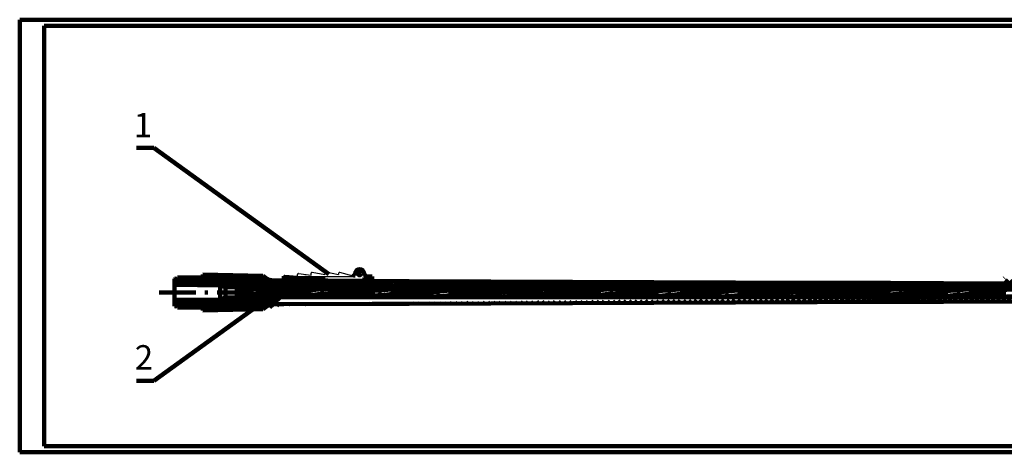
# Model space of a CAD drawing. Units: inches. Extents: x -7.8 to 42.6, y -11.6 to 2.6.
# Drawn here: x -7.8 to 24.5, y -11.6 to 2.6 of the extents above; entities that cross this region are included whole.
import ezdxf

# ---------------------------------------------------------------- set-up
doc = ezdxf.new("R2010")
doc.units = ezdxf.units.IN
doc.header["$LTSCALE"] = 0.1
doc.header["$MEASUREMENT"] = 0
doc.linetypes.add('ACAD_ISO10W100', pattern=[18, 12, -3, 0, -3])

# ---------------------------------------------------------------- blocks, each defined once
blk = doc.blocks.new('_dragoon__1896')
at = {"lineweight": 25, "ltscale": 0.7}
h = blk.add_hatch(dxfattribs=at)
h.set_pattern_fill('ANSI31', scale=0.25, angle=90, style=0)
h.paths.add_polyline_path([(-0.708, -27.192), (-0.708, -27.127), (-1.353, -27.127), (-1.353, -27.187)])
h.paths.add_polyline_path([(-0.708, -27.192), (-0.692, -27.192), (-0.692, -27.127), (-0.708, -27.127)])
h.paths.add_polyline_path([(-0.599, -27.193), (-0.583, -27.193), (-0.583, -27.127), (-0.599, -27.127)])
h.paths.add_polyline_path([(-0.003, -27.198), (-0.003, -27.162), (-0.378, -27.127), (-0.583, -27.127), (-0.583, -27.193)])
h.paths.add_polyline_path([(1.347, -27.068), (1.316, -27.068, -0.044213), (1.297, -27.098), (1.297, -27.207), (1.547, -27.209), (1.547, -27.068)])
at = {"color": 7, "lineweight": 140, "ltscale": 1.4}
for p, q in [((-1.353, -27.187), (-1.353, -27.06)), ((-0.378, -27.127), (-1.353, -27.127)), ((-0.003, -27.162), (-0.378, -27.127)), ((-0.003, -27.198), (-0.003, -27.162)), ((0.987, -27.028), (0.954, -27.028)), ((0.987, -27.028), (0.987, -26.978)), ((1.287, -27.028), (1.287, -26.978)), ((1.287, -27.028), (1.32, -27.028)), ((1.297, -27.098), (1.297, -27.207)), ((1.347, -27.068), (1.316, -27.068)), ((1.347, -27.055), (1.347, -27.068)), ((1.547, -27.068), (1.347, -27.068)), ((1.547, -27.068), (1.547, -27.209)), ((0.447, -27.588), (0.927, -27.588)), ((0.927, -27.588), (1.636, -27.588))]:
    blk.add_line(p, q, dxfattribs=at)
at = {"color": 7, "lineweight": 25, "ltscale": 0.7}
for p, q in [((-1.353, -27.067), (-0.924, -27.067)), ((-0.903, -27.069), (-1.32, -27.03)), ((-0.903, -27.069), (-0.903, -26.999)), ((-0.903, -27.067), (0.483, -27.067)), ((-0.869, -26.969), (-0.453, -27.022)), ((-0.692, -27.127), (-0.692, -27.192)), ((-0.599, -27.127), (-0.599, -27.193)), ((-0.453, -27.022), (-0.453, -26.958)), ((-0.418, -26.928), (-0.003, -26.998)), ((-0.378, -27.127), (-0.333, -27.127)), ((-0.333, -27.127), (-0.373, -27.067)), ((-0.003, -26.944), (-0.003, -26.998)), ((0.034, -26.914), (0.447, -27.005)), ((0.447, -26.964), (0.447, -27.005)), ((0.483, -27.067), (0.915, -27.067)), ((0.927, -27.059), (0.486, -26.935)), ((0.927, -27.055), (0.927, -27.055))]:
    blk.add_line(p, q, dxfattribs=at)
at = {"color": 7, "lineweight": 25, "ltscale": 0.25}
for p, q in [((-0.708, -27.127), (-0.708, -27.192)), ((-0.583, -27.127), (-0.583, -27.193))]:
    blk.add_line(p, q, dxfattribs=at)
at = {"color": 1, "linetype": 'ACAD_ISO10W100', "lineweight": 25, "ltscale": 0.25}
blk.add_line((-0.645, -27.045), (-0.645, -27.277), dxfattribs=at)
at = {"color": 7, "lineweight": 100, "ltscale": 1.4}
for p, q in [((-1.353, -27.199), (-1.353, -27.187)), ((-1.353, -27.187), (1.547, -27.209))]:
    blk.add_line(p, q, dxfattribs=at)
at = {"color": 7, "lineweight": 140, "ltscale": 1.4}
blk.add_circle((1.137, -26.978), 0.05, dxfattribs=at)
for centre, radius, start, end in [((1.137, -26.978), 0.15, 0, 180), ((0.954, -27.055), 0.027, 90, 180), ((1.137, -26.978), 0.2, 323.1301, 333.2563), ((1.32, -27.055), 0.027, 360, 90)]:
    blk.add_arc(centre, radius, start, end, dxfattribs=at)
at = {"color": 7, "lineweight": 25, "ltscale": 0.7}
for centre, radius, start, end in [((-1.323, -27.06), 0.03, 84.6047, 180), ((-0.873, -26.999), 0.03, 82.7183, 180), ((-0.423, -26.958), 0.03, 80.4138, 180), ((0.027, -26.944), 0.03, 77.5926, 180), ((0.477, -26.964), 0.03, 74.2914, 180), ((0.915, -27.055), 0.012, 270, 0)]:
    blk.add_arc(centre, radius, start, end, dxfattribs=at)

msp = doc.modelspace()

# ---------------------------------------------------------------- hatches: boundary and pattern name
at = {"lineweight": 100, "ltscale": 1.4}
h = msp.add_hatch(dxfattribs=at)
h.set_pattern_fill('ANSI31', style=0)
edge = h.paths.add_edge_path()
edge.add_line((-1.22, -6.109), (-2.72, -6.093))
edge.add_line((-2.72, -5.89), (-2.645, -5.89))
edge.add_line((-2.625, -5.85), (-2.645, -5.89))
edge.add_line((-1.789, -5.85), (-2.625, -5.85))
edge.add_line((-1.789, -5.85), (-1.789, -5.749))
edge.add_line((-1.789, -5.749), (0.18, -5.789))
edge.add_arc((0.57, -5.393), 0.556, 225.4044, 270.9928)
edge.add_line((0.58, -5.949), (0.87, -5.95))
edge.add_line((0.87, -5.938), (3.77, -5.96))
edge.add_line((3.77, -5.96), (4.986, -5.965))
edge.add_line((18.386, -6.019), (4.986, -5.965))
edge.add_line((20.8, -6.028), (18.386, -6.019))
edge.add_line((20.8, -6.028), (22.531, -6.034))
edge.add_line((24.533, -6.041), (22.531, -6.034))
edge.add_line((24.533, -6.041), (24.533, -5.864))
edge.add_line((24.675, -5.864), (24.533, -5.864))
edge.add_line((24.675, -5.864), (24.65, -5.944))
edge.add_line((24.65, -5.944), (24.85, -5.944))
edge.add_line((24.85, -5.944), (24.825, -5.864))
edge.add_line((24.825, -5.864), (24.97, -5.864))
edge.add_line((24.97, -6.043), (24.97, -5.864))
edge.add_line((25.955, -6.046), (24.97, -6.043))
edge.add_arc((25.955, -6.121), 0.075, 0, 90)
edge.add_line((26.03, -6.189), (0.16, -6.189))
edge.add_line((0.16, -6.189), (-0.55, -6.183))
edge.add_line((-0.55, -6.183), (-0.67, -6.17))
edge.add_line((-0.67, -6.17), (-1.04, -6.169))
edge.add_line((-1.04, -6.169), (-1.22, -6.109))
h.paths.add_polyline_path([(11.1, -1.279), (12.21, -1.279), (12.21, -1.549), (11.1, -1.549)], flags=9)
h = msp.add_hatch(dxfattribs=at)
h.set_pattern_fill('ANSI31', style=0)
edge = h.paths.add_edge_path()
edge.add_line((-2.72, -6.584), (-2.72, -6.788))
edge.add_line((-2.72, -6.584), (-1.22, -6.569))
edge.add_line((-2.72, -6.788), (-1.789, -6.788))
edge.add_line((-2.625, -6.828), (-2.645, -6.788))
edge.add_line((-1.789, -6.828), (-2.625, -6.828))
edge.add_line((-1.789, -6.828), (-1.789, -6.929))
edge.add_line((-1.789, -6.929), (0.18, -6.889))
edge.add_line((-1.04, -6.508), (-1.22, -6.569))
edge.add_line((-0.67, -6.507), (-1.04, -6.508))
edge.add_line((-0.55, -6.495), (-0.67, -6.507))
edge.add_line((0.16, -6.489), (-0.55, -6.495))
edge.add_arc((0.946, 12.191), 18.68, 270, 272.658)
edge.add_line((0.16, -6.489), (26.03, -6.489))
edge.add_arc((0.57, -7.284), 0.556, 89.0072, 134.5956)
edge.add_line((0.87, -6.728), (0.58, -6.729))
edge.add_line((0.87, -6.728), (3.77, -6.718))
edge.add_line((4.986, -6.713), (3.77, -6.718))
edge.add_line((4.986, -6.713), (18.386, -6.659))
edge.add_line((20.8, -6.649), (18.386, -6.659))
edge.add_line((20.8, -6.649), (22.531, -6.643))
edge.add_line((25.955, -6.631), (22.531, -6.643))
edge.add_arc((25.955, -6.556), 0.075, 270, 360)

# ---------------------------------------------------------------- linework, layer by layer
at = {"color": 7, "lineweight": 100, "ltscale": 1.4}
for p, q in [((42.6, 2.612), (-7.804, 2.612)), ((-7.804, 2.612), (-7.804, -11.585)), ((42.4, 2.412), (-7.004, 2.412)), ((-7.004, 2.412), (-7.004, -11.385)), ((-3.4, -1.591), (-3.963, -1.591)), ((-3.4, -1.591), (2.353, -5.74)), ((-1.789, -5.749), (0.18, -5.789)), ((-1.789, -5.85), (-1.789, -5.749)), ((-2.72, -6.093), (-2.491, -5.85)), ((-2.72, -5.89), (-2.645, -5.89)), ((-2.72, -5.89), (-2.72, -6.093)), ((-1.22, -6.109), (-2.72, -6.093)), ((-2.72, -6.093), (-2.72, -6.584)), ((-2.625, -5.85), (-2.645, -5.89)), ((-1.789, -5.85), (-2.625, -5.85)), ((-1.22, -6.339), (-1.22, -6.109)), ((-1.22, -6.109), (-1.22, -6.569)), ((-1.04, -6.169), (-1.22, -6.109)), ((0.58, -5.949), (0.87, -5.95)), ((0.87, -5.95), (0.87, -5.938)), ((0.87, -5.938), (3.77, -5.96)), ((-1.04, -6.339), (-1.04, -6.169)), ((-1.04, -6.169), (-1.04, -6.508)), ((-0.67, -6.17), (-1.04, -6.169)), ((-0.67, -6.339), (-0.67, -6.17)), ((-0.67, -6.17), (-0.67, -6.507)), ((-0.55, -6.183), (-0.67, -6.17)), ((-0.55, -6.339), (-0.55, -6.183)), ((-0.55, -6.183), (-0.55, -6.495)), ((0.16, -6.189), (-0.55, -6.183)), ((0.16, -6.339), (0.16, -6.189)), ((0.16, -6.189), (0.16, -6.489)), ((0.16, -6.189), (0.16, -6.489)), ((26.03, -6.189), (0.16, -6.189)), ((-3.4, -9.244), (0.15, -6.68)), ((-2.72, -6.584), (-1.22, -6.569)), ((-2.72, -6.584), (-2.72, -6.788)), ((-2.72, -6.788), (-2.645, -6.788)), ((-2.625, -6.828), (-2.645, -6.788)), ((-1.04, -6.508), (-1.22, -6.569)), ((-0.67, -6.507), (-1.04, -6.508)), ((-0.55, -6.495), (-0.67, -6.507)), ((0.16, -6.489), (-0.55, -6.495)), ((0.16, -6.489), (26.03, -6.489)), ((0.87, -6.728), (0.58, -6.729)), ((0.87, -6.728), (3.77, -6.718)), ((-1.789, -6.828), (-2.625, -6.828)), ((-1.789, -6.828), (-1.789, -6.929)), ((-1.789, -6.929), (0.18, -6.889)), ((-3.4, -9.244), (-3.963, -9.244)), ((-7.804, -11.585), (-7.804, -11.385)), ((-7.004, -11.585), (-7.804, -11.585)), ((-7.804, -11.585), (42.6, -11.585)), ((35, -11.385), (-7.004, -11.385)), ((-7.004, -11.585), (42.6, -11.585))]:
    msp.add_line(p, q, dxfattribs=at)
at = {"color": 7, "lineweight": 50, "ltscale": 0.7}
for p, q in [((-2.645, -5.89), (-1.789, -5.89)), ((-1.789, -5.89), (-1.789, -5.85)), ((-2.72, -6.788), (-1.789, -6.788)), ((-1.789, -6.788), (-1.789, -6.828))]:
    msp.add_line(p, q, dxfattribs=at)
at = {"color": 7, "lineweight": 140, "ltscale": 1.4}
for p, q in [((3.77, -5.96), (4.986, -5.965)), ((18.386, -6.019), (4.986, -5.965)), ((20.8, -6.028), (18.386, -6.019)), ((20.8, -6.028), (22.531, -6.034)), ((24.533, -6.041), (22.531, -6.034)), ((4.986, -6.713), (3.77, -6.718)), ((4.986, -6.713), (18.386, -6.659)), ((20.8, -6.649), (18.386, -6.659)), ((20.8, -6.649), (22.531, -6.643)), ((25.955, -6.631), (22.531, -6.643))]:
    msp.add_line(p, q, dxfattribs=at)
at = {"color": 1, "linetype": 'ACAD_ISO10W100', "lineweight": 100}
msp.add_line((-3.22, -6.339), (26.933, -6.339), dxfattribs=at)
at = {"color": 7, "lineweight": 100, "ltscale": 1.4}
for centre, radius, start, end in [((0.57, -5.393), 0.556, 225.4044, 270.9928), ((1.122, -24.868), 18.68, 90, 95.136), ((0.316, -24.868), 18.68, 90, 92.658), ((-1.417, 12.191), 18.68, 272.658, 277.2659), ((-2.223, 12.191), 18.68, 275.136, 277.2659), ((2.421, -24.878), 18.68, 91.8663, 97.0145), ((0.14, 12.191), 18.68, 270, 275.136), ((2.988, -24.906), 18.68, 93.6038, 96.2753), ((2.68, -24.868), 18.68, 90, 92.658), ((3.486, -24.868), 18.68, 90, 95.136), ((0.141, 12.191), 18.68, 275.136, 277.2659), ((0.947, 12.191), 18.68, 272.658, 277.2659), ((4.785, -24.878), 18.68, 91.8663, 97.0145), ((2.504, 12.191), 18.68, 270, 275.136), ((5.352, -24.906), 18.68, 93.6038, 96.2753), ((5.848, -24.868), 18.68, 90, 95.136), ((5.042, -24.868), 18.68, 90, 92.658), ((3.31, 12.191), 18.68, 272.658, 277.2659), ((2.504, 12.191), 18.68, 275.136, 277.2659), ((7.147, -24.878), 18.68, 91.8663, 97.0145), ((4.866, 12.191), 18.68, 270, 275.136), ((7.714, -24.906), 18.68, 93.6038, 96.2753), ((8.209, -24.868), 18.68, 90, 95.136), ((7.403, -24.868), 18.68, 90, 92.658), ((5.671, 12.191), 18.68, 272.658, 277.2659), ((4.865, 12.191), 18.68, 275.136, 277.2659), ((9.508, -24.878), 18.68, 91.8663, 97.0145), ((7.227, 12.191), 18.68, 270, 275.136), ((10.075, -24.906), 18.68, 93.6038, 96.2753), ((9.766, -24.868), 18.68, 90, 92.658), ((10.572, -24.868), 18.68, 90, 95.136), ((7.227, 12.191), 18.68, 275.136, 277.2659), ((8.033, 12.191), 18.68, 272.658, 277.2659), ((11.871, -24.878), 18.68, 91.8663, 97.0145), ((9.59, 12.191), 18.68, 270, 275.136), ((12.438, -24.906), 18.68, 93.6038, 96.2753), ((12.934, -24.868), 18.68, 90, 95.136), ((12.128, -24.868), 18.68, 90, 92.658), ((10.396, 12.191), 18.68, 272.658, 277.2659), ((9.59, 12.191), 18.68, 275.136, 277.2659), ((14.233, -24.878), 18.68, 91.8663, 97.0145), ((11.952, 12.191), 18.68, 270, 275.136), ((14.8, -24.906), 18.68, 93.6038, 96.2753), ((14.491, -24.868), 18.68, 90, 92.658), ((15.297, -24.868), 18.68, 90, 95.136), ((12.758, 12.191), 18.68, 272.658, 277.2659), ((11.952, 12.191), 18.68, 275.136, 277.2659), ((16.596, -24.878), 18.68, 91.8663, 97.0145), ((14.315, 12.191), 18.68, 270, 275.136), ((17.163, -24.906), 18.68, 93.6038, 96.2753), ((17.659, -24.868), 18.68, 90, 95.136), ((16.853, -24.868), 18.68, 90, 92.658), ((15.121, 12.191), 18.68, 272.658, 277.2659), ((14.315, 12.191), 18.68, 275.136, 277.2659), ((18.958, -24.878), 18.68, 91.8663, 97.0145), ((16.677, 12.191), 18.68, 270, 275.136), ((19.525, -24.906), 18.68, 93.6038, 96.2753), ((20.022, -24.868), 18.68, 90, 95.136), ((19.216, -24.868), 18.68, 90, 92.658), ((17.483, 12.191), 18.68, 272.658, 277.2659), ((16.677, 12.191), 18.68, 275.136, 277.2659), ((21.321, -24.878), 18.68, 91.8663, 97.0145), ((19.04, 12.191), 18.68, 270, 275.136), ((21.888, -24.906), 18.68, 93.6038, 96.2753), ((21.578, -24.868), 18.68, 90, 92.658), ((22.384, -24.868), 18.68, 90, 95.136), ((19.04, 12.191), 18.68, 275.136, 277.2659), ((19.846, 12.191), 18.68, 272.658, 277.2659), ((23.683, -24.878), 18.68, 91.8663, 97.0145), ((21.402, 12.191), 18.68, 270, 275.136), ((24.25, -24.906), 18.68, 93.6038, 96.2753), ((24.747, -24.868), 18.68, 90, 95.136), ((23.941, -24.868), 18.68, 90, 92.658), ((22.208, 12.191), 18.68, 272.658, 277.2659), ((21.402, 12.191), 18.68, 275.136, 277.2659), ((26.046, -24.878), 18.68, 91.8663, 97.0145), ((23.765, 12.191), 18.68, 270, 275.136), ((0.57, -7.284), 0.556, 89.0072, 134.5956), ((0.946, 12.191), 18.68, 270, 272.658), ((3.31, 12.191), 18.68, 270, 272.658), ((5.672, 12.191), 18.68, 270, 272.658), ((8.033, 12.191), 18.68, 270, 272.658), ((10.396, 12.191), 18.68, 270, 272.658), ((12.758, 12.191), 18.68, 270, 272.658), ((15.121, 12.191), 18.68, 270, 272.658), ((17.483, 12.191), 18.68, 270, 272.658), ((19.846, 12.191), 18.68, 270, 272.658), ((22.208, 12.191), 18.68, 270, 272.658)]:
    msp.add_arc(centre, radius, start, end, dxfattribs=at)

# ---------------------------------------------------------------- block references
msp.add_blockref('_dragoon__1896', (2.222, 21.25), dxfattribs=at)

# ---------------------------------------------------------------- texts
for s, p in [('1', (-4.057, -1.248)), ('2', (-4.026, -8.869))]:
    msp.add_text(s, height=0.8, dxfattribs=at).set_placement(p)

doc.saveas('drawing.dxf')
